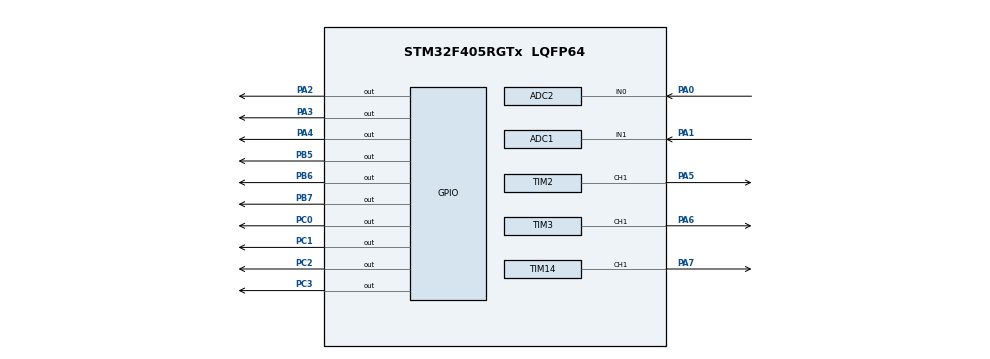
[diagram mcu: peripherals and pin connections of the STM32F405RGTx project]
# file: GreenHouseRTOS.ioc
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ADC1.Channel-0\#ChannelRegularConversion=ADC_CHANNEL_1
ADC1.ContinuousConvMode=ENABLE
ADC1.NbrOfConversionFlag=1
ADC1.Rank-0\#ChannelRegularConversion=1
ADC1.SamplingTime-0\#ChannelRegularConversion=ADC_SAMPLETIME_3CYCLES
ADC1.master=1
ADC2.Channel-0\#ChannelRegularConversion=ADC_CHANNEL_0
ADC2.NbrOfConversionFlag=1
ADC2.Rank-0\#ChannelRegularConversion=1
ADC2.SamplingTime-0\#ChannelRegularConversion=ADC_SAMPLETIME_3CYCLES
FREERTOS.Tasks01=defaultTask,0,128,StartDefaultTask,Default,NULL,Dynamic,NULL,NULL
FREERTOS.configCHECK_FOR_STACK_OVERFLOW=1
FREERTOS.configGENERATE_RUN_TIME_STATS=1
FREERTOS.configMAX_TASK_NAME_LEN=25
FREERTOS.configRECORD_STACK_HIGH_ADDRESS=1
FREERTOS.configUSE_IDLE_HOOK=1
FREERTOS.configUSE_NEWLIB_REENTRANT=1
FREERTOS.configUSE_STATS_FORMATTING_FUNCTIONS=1
FREERTOS.configUSE_TICK_HOOK=1
FREERTOS.configUSE_TRACE_FACILITY=1
Mcu.Family=STM32F4
Mcu.Name=STM32F405RGTx
Mcu.Package=LQFP64
NVIC.PriorityGroup=NVIC_PRIORITYGROUP_4
PA0-WKUP.Signal=ADCx_IN0
PA1.Signal=ADCx_IN1
PA2.Signal=GPIO_Output
PA3.Signal=GPIO_Output
PA4.Signal=GPIO_Output
PA5.Signal=S_TIM2_CH1_ETR
PA6.Signal=S_TIM3_CH1
PA7.Signal=S_TIM14_CH1
PB5.Signal=GPIO_Output
PB6.Signal=GPIO_Output
PB7.Signal=GPIO_Output
PC0.Signal=GPIO_Output
PC1.Signal=GPIO_Output
PC2.Signal=GPIO_Output
PC3.Signal=GPIO_Output
ProjectManager.HeapSize=0x200
ProjectManager.StackSize=0x400
ProjectManager.TargetToolchain=STM32CubeIDE
RCC.48MHZClocksFreq_Value=32000000
RCC.AHBCLKDivider=RCC_SYSCLK_DIV4
RCC.AHBFreq_Value=16000000
RCC.APB1CLKDivider=RCC_HCLK_DIV2
RCC.APB1Freq_Value=8000000
RCC.APB1TimFreq_Value=16000000
RCC.APB2Freq_Value=16000000
RCC.APB2TimFreq_Value=16000000
RCC.CortexFreq_Value=16000000
RCC.HCLKFreq_Value=16000000
RCC.HSE_VALUE=25000000
RCC.HSI_VALUE=16000000
RCC.LSE_VALUE=32768
RCC.PLLM=8
RCC.PLLN=64
RCC.SYSCLKFreq_VALUE=64000000
RCC.SYSCLKSource=RCC_SYSCLKSOURCE_PLLCLK
RCC.VCOOutputFreq_Value=128000000
SH.ADCx_IN0.0=ADC2_IN0,IN0
SH.ADCx_IN1.0=ADC1_IN1,IN1
SH.S_TIM14_CH1.0=TIM14_CH1,PWM Generation1 CH1
SH.S_TIM2_CH1_ETR.0=TIM2_CH1,PWM Generation1 CH1
SH.S_TIM3_CH1.0=TIM3_CH1,PWM Generation1 CH1
TIM12.Prescaler=15
TIM14.Channel=TIM_CHANNEL_1
TIM14.OCFastMode_PWM=TIM_OCFAST_ENABLE
TIM14.Period=799
TIM14.Prescaler=1
TIM2.Channel-PWM\ Generation1\ CH1=TIM_CHANNEL_1
TIM2.OCFastMode_PWM-PWM\ Generation1\ CH1=TIM_OCFAST_ENABLE
TIM2.Period=99
TIM2.Prescaler=15
TIM3.Channel-PWM\ Generation1\ CH1=TIM_CHANNEL_1
TIM3.OCFastMode_PWM-PWM\ Generation1\ CH1=TIM_OCFAST_ENABLE
TIM3.Period=9
TIM3.Prescaler=159
VP_FREERTOS_VS_CMSIS_V1.Mode=CMSIS_V1
VP_TIM12_VS_ClockSourceINT.Mode=Internal
VP_TIM14_VS_ClockSourceINT.Mode=Enable_Timer
VP_TIM2_VS_ClockSourceINT.Mode=Internal
VP_TIM3_VS_ClockSourceINT.Mode=Internal
board=custom

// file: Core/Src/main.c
/* USER CODE BEGIN Header */
/**
 ******************************************************************************
 * @file           : main.c
 * @brief          : Main program body
 ******************************************************************************
 * @attention
 *
 * Copyright (c) 2025 STMicroelectronics.
 * All rights reserved.
 *
 * This software is licensed under terms that can be found in the LICENSE file
 * in the root directory of this software component.
 * If no LICENSE file comes with this software, it is provided AS-IS.
 *
 ******************************************************************************
 */
/* USER CODE END Header */
#include "main.h"
#include "cmsis_os.h"

/* USER CODE BEGIN Includes */
#include<stdio.h>
#include "dht11.h"
#include "stdint.h"
#include "string.h"
#include "math.h"
/* USER CODE END Includes */

/* USER CODE BEGIN PD */
#define SOIL_MOISTURE_THRESHOLD 4050
#define LDR_HIGH_THRESHOLD 3200
#define LDR_MEDIUM_THRESHOLD 2500
#define LDR_LOW_THRESHOLD 1800
#define PWM_MAX 600
#define PWM_MEDIUM 400
#define PWM_LOW 200
#define PWM_MIN 0
#define PWM_INIT 0
/* USER CODE END PD */

ADC_HandleTypeDef hadc1;
ADC_HandleTypeDef hadc2;

TIM_HandleTypeDef htim2;
TIM_HandleTypeDef htim3;
TIM_HandleTypeDef htim12;
TIM_HandleTypeDef htim14;

osThreadId defaultTaskHandle;
/* USER CODE BEGIN PV */
TaskHandle_t x1Handle;
TaskHandle_t x2Handle;
TaskHandle_t x3Handle;
BaseType_t x1Return;
BaseType_t x2Return;
BaseType_t x3Return;

uint32_t analogIn = 0;
uint8_t check;
float moisture_percent = 0;
uint8_t DHT11_Read(DHT11_Data *data);
DHT11_Data dht;
uint8_t flag = 0;
uint32_t ldr_value = 0;
/* USER CODE END PV */

void SystemClock_Config(void);
static void MX_GPIO_Init(void);
static void MX_ADC1_Init(void);
static void MX_TIM2_Init(void);
static void MX_TIM3_Init(void);
static void MX_TIM14_Init(void);
static void MX_ADC2_Init(void);
static void MX_TIM12_Init(void);
void StartDefaultTask(void const * argument);

/* USER CODE BEGIN PFP */
void soilMoisture(void *pvParameters);
void tempHum(void *pvParameters);
void ldrMonitor(void *pvParameters);
void motor_config(void);
void led_pwm_config(void);
/* USER CODE END PFP */

int main(void)
{

  /* MCU Configuration--------------------------------------------------------*/

  /* Reset of all peripherals, Initializes the Flash interface and the Systick. */
  HAL_Init();

  /* Configure the system clock */
  SystemClock_Config();

  /* Initialize all configured peripherals */
  MX_GPIO_Init();
  MX_ADC1_Init();
  MX_TIM2_Init();
  MX_TIM3_Init();
  MX_TIM14_Init();
  MX_ADC2_Init();
  MX_TIM12_Init();
  /* USER CODE BEGIN 2 */
	HAL_ADC_Start(&hadc1);
	HAL_ADC_Start(&hadc2);
	HAL_TIM_PWM_Start(&htim3, TIM_CHANNEL_1);
	HAL_TIM_PWM_Start(&htim14, TIM_CHANNEL_1);
	HAL_TIM_PWM_Start(&htim2, TIM_CHANNEL_1); // Start PWM

	HAL_TIM_Base_Start(&htim12);
	DWT_Init();

	motor_config();
	led_pwm_config();
  /* USER CODE END 2 */

  /* Create the thread(s) */
  /* definition and creation of defaultTask */
  osThreadDef(defaultTask, StartDefaultTask, osPriorityNormal, 0, 128);
  defaultTaskHandle = osThreadCreate(osThread(defaultTask), NULL);

  /* USER CODE BEGIN RTOS_THREADS */
	/* add threads, ... */
	x1Return = xTaskCreate(soilMoisture, "SOIL TASK",
	configMINIMAL_STACK_SIZE * 3,
	NULL, 2, &x1Handle);

	x2Return = xTaskCreate(tempHum, "T&H TASK",
	configMINIMAL_STACK_SIZE * 3,
	NULL, 1, &x2Handle);

	x3Return = xTaskCreate(ldrMonitor, "LIGHT TASK",
	configMINIMAL_STACK_SIZE * 3,
	NULL, 1, &x3Handle);
  /* USER CODE END RTOS_THREADS */

  /* Start scheduler */
  osKernelStart();

  /* We should never get here as control is now taken by the scheduler */
  /* Infinite loop */
	while (1) {

	}
}

void SystemClock_Config(void)
{
	RCC_OscInitTypeDef RCC_OscInitStruct = {0};
	  RCC_ClkInitTypeDef RCC_ClkInitStruct = {0};

	  /** Configure the main internal regulator output voltage
	  */
	  __HAL_RCC_PWR_CLK_ENABLE();
	  __HAL_PWR_VOLTAGESCALING_CONFIG(PWR_REGULATOR_VOLTAGE_SCALE1);

	  /** Initializes the RCC Oscillators according to the specified parameters
	  * in the RCC_OscInitTypeDef structure.
	  */
	  RCC_OscInitStruct.OscillatorType = RCC_OSCILLATORTYPE_HSI;
	  RCC_OscInitStruct.HSIState = RCC_HSI_ON;
	  RCC_OscInitStruct.HSICalibrationValue = RCC_HSICALIBRATION_DEFAULT;
	  RCC_OscInitStruct.PLL.PLLState = RCC_PLL_ON;
	  RCC_OscInitStruct.PLL.PLLSource = RCC_PLLSOURCE_HSI;
	  RCC_OscInitStruct.PLL.PLLM = 8;
	  RCC_OscInitStruct.PLL.PLLN = 84;
	  RCC_OscInitStruct.PLL.PLLP = RCC_PLLP_DIV4;
	  RCC_OscInitStruct.PLL.PLLQ = 4;
	  if (HAL_RCC_OscConfig(&RCC_OscInitStruct) != HAL_OK)
	  {
	    Error_Handler();
	  }

	  /** Initializes the CPU, AHB and APB buses clocks
	  */
	  RCC_ClkInitStruct.ClockType = RCC_CLOCKTYPE_HCLK|RCC_CLOCKTYPE_SYSCLK
	                              |RCC_CLOCKTYPE_PCLK1|RCC_CLOCKTYPE_PCLK2;
	  RCC_ClkInitStruct.SYSCLKSource = RCC_SYSCLKSOURCE_PLLCLK;
	  RCC_ClkInitStruct.AHBCLKDivider = RCC_SYSCLK_DIV1;
	  RCC_ClkInitStruct.APB1CLKDivider = RCC_HCLK_DIV1;
	  RCC_ClkInitStruct.APB2CLKDivider = RCC_HCLK_DIV1;

	  if (HAL_RCC_ClockConfig(&RCC_ClkInitStruct, FLASH_LATENCY_1) != HAL_OK)
	  {
	    Error_Handler();
	  }

}

static void MX_ADC1_Init(void)
{

  ADC_ChannelConfTypeDef sConfig = {0};

  /** Configure the global features of the ADC (Clock, Resolution, Data Alignment and number of conversion)
  */
  hadc1.Instance = ADC1;
  hadc1.Init.ClockPrescaler = ADC_CLOCK_SYNC_PCLK_DIV2;
  hadc1.Init.Resolution = ADC_RESOLUTION_12B;
  hadc1.Init.ScanConvMode = DISABLE;
  hadc1.Init.ContinuousConvMode = ENABLE;
  hadc1.Init.DiscontinuousConvMode = DISABLE;
  hadc1.Init.ExternalTrigConvEdge = ADC_EXTERNALTRIGCONVEDGE_NONE;
  hadc1.Init.ExternalTrigConv = ADC_SOFTWARE_START;
  hadc1.Init.DataAlign = ADC_DATAALIGN_RIGHT;
  hadc1.Init.NbrOfConversion = 1;
  hadc1.Init.DMAContinuousRequests = DISABLE;
  hadc1.Init.EOCSelection = ADC_EOC_SINGLE_CONV;
  if (HAL_ADC_Init(&hadc1) != HAL_OK)
  {
    Error_Handler();
  }

  /** Configure for the selected ADC regular channel its corresponding rank in the sequencer and its sample time.
  */
  sConfig.Channel = ADC_CHANNEL_1;
  sConfig.Rank = 1;
  sConfig.SamplingTime = ADC_SAMPLETIME_3CYCLES;
  if (HAL_ADC_ConfigChannel(&hadc1, &sConfig) != HAL_OK)
  {
    Error_Handler();
  }

}

static void MX_ADC2_Init(void)
{

  ADC_ChannelConfTypeDef sConfig = {0};

  /** Configure the global features of the ADC (Clock, Resolution, Data Alignment and number of conversion)
  */
  hadc2.Instance = ADC2;
  hadc2.Init.ClockPrescaler = ADC_CLOCK_SYNC_PCLK_DIV2;
  hadc2.Init.Resolution = ADC_RESOLUTION_12B;
  hadc2.Init.ScanConvMode = DISABLE;
  hadc2.Init.ContinuousConvMode = DISABLE;
  hadc2.Init.DiscontinuousConvMode = DISABLE;
  hadc2.Init.ExternalTrigConvEdge = ADC_EXTERNALTRIGCONVEDGE_NONE;
  hadc2.Init.ExternalTrigConv = ADC_SOFTWARE_START;
  hadc2.Init.DataAlign = ADC_DATAALIGN_RIGHT;
  hadc2.Init.NbrOfConversion = 1;
  hadc2.Init.DMAContinuousRequests = DISABLE;
  hadc2.Init.EOCSelection = ADC_EOC_SINGLE_CONV;
  if (HAL_ADC_Init(&hadc2) != HAL_OK)
  {
    Error_Handler();
  }

  /** Configure for the selected ADC regular channel its corresponding rank in the sequencer and its sample time.
  */
  sConfig.Channel = ADC_CHANNEL_0;
  sConfig.Rank = 1;
  sConfig.SamplingTime = ADC_SAMPLETIME_3CYCLES;
  if (HAL_ADC_ConfigChannel(&hadc2, &sConfig) != HAL_OK)
  {
    Error_Handler();
  }

}

static void MX_TIM2_Init(void)
{

  TIM_ClockConfigTypeDef sClockSourceConfig = {0};
  TIM_MasterConfigTypeDef sMasterConfig = {0};
  TIM_OC_InitTypeDef sConfigOC = {0};

  htim2.Instance = TIM2;
  htim2.Init.Prescaler = 15;
  htim2.Init.CounterMode = TIM_COUNTERMODE_UP;
  htim2.Init.Period = 99;
  htim2.Init.ClockDivision = TIM_CLOCKDIVISION_DIV1;
  htim2.Init.AutoReloadPreload = TIM_AUTORELOAD_PRELOAD_DISABLE;
  if (HAL_TIM_Base_Init(&htim2) != HAL_OK)
  {
    Error_Handler();
  }
  sClockSourceConfig.ClockSource = TIM_CLOCKSOURCE_INTERNAL;
  if (HAL_TIM_ConfigClockSource(&htim2, &sClockSourceConfig) != HAL_OK)
  {
    Error_Handler();
  }
  if (HAL_TIM_PWM_Init(&htim2) != HAL_OK)
  {
    Error_Handler();
  }
  sMasterConfig.MasterOutputTrigger = TIM_TRGO_RESET;
  sMasterConfig.MasterSlaveMode = TIM_MASTERSLAVEMODE_DISABLE;
  if (HAL_TIMEx_MasterConfigSynchronization(&htim2, &sMasterConfig) != HAL_OK)
  {
    Error_Handler();
  }
  sConfigOC.OCMode = TIM_OCMODE_PWM1;
  sConfigOC.Pulse = 0;
  sConfigOC.OCPolarity = TIM_OCPOLARITY_HIGH;
  sConfigOC.OCFastMode = TIM_OCFAST_ENABLE;
  if (HAL_TIM_PWM_ConfigChannel(&htim2, &sConfigOC, TIM_CHANNEL_1) != HAL_OK)
  {
    Error_Handler();
  }
  HAL_TIM_MspPostInit(&htim2);

}

static void MX_TIM3_Init(void)
{

  TIM_ClockConfigTypeDef sClockSourceConfig = {0};
  TIM_MasterConfigTypeDef sMasterConfig = {0};
  TIM_OC_InitTypeDef sConfigOC = {0};

  htim3.Instance = TIM3;
  htim3.Init.Prescaler = 159;
  htim3.Init.CounterMode = TIM_COUNTERMODE_UP;
  htim3.Init.Period = 9;
  htim3.Init.ClockDivision = TIM_CLOCKDIVISION_DIV1;
  htim3.Init.AutoReloadPreload = TIM_AUTORELOAD_PRELOAD_DISABLE;
  if (HAL_TIM_Base_Init(&htim3) != HAL_OK)
  {
    Error_Handler();
  }
  sClockSourceConfig.ClockSource = TIM_CLOCKSOURCE_INTERNAL;
  if (HAL_TIM_ConfigClockSource(&htim3, &sClockSourceConfig) != HAL_OK)
  {
    Error_Handler();
  }
  if (HAL_TIM_PWM_Init(&htim3) != HAL_OK)
  {
    Error_Handler();
  }
  sMasterConfig.MasterOutputTrigger = TIM_TRGO_RESET;
  sMasterConfig.MasterSlaveMode = TIM_MASTERSLAVEMODE_DISABLE;
  if (HAL_TIMEx_MasterConfigSynchronization(&htim3, &sMasterConfig) != HAL_OK)
  {
    Error_Handler();
  }
  sConfigOC.OCMode = TIM_OCMODE_PWM1;
  sConfigOC.Pulse = 0;
  sConfigOC.OCPolarity = TIM_OCPOLARITY_HIGH;
  sConfigOC.OCFastMode = TIM_OCFAST_ENABLE;
  if (HAL_TIM_PWM_ConfigChannel(&htim3, &sConfigOC, TIM_CHANNEL_1) != HAL_OK)
  {
    Error_Handler();
  }
  HAL_TIM_MspPostInit(&htim3);

}

static void MX_TIM12_Init(void)
{

  TIM_ClockConfigTypeDef sClockSourceConfig = {0};

  htim12.Instance = TIM12;
  htim12.Init.Prescaler = 15;
  htim12.Init.CounterMode = TIM_COUNTERMODE_UP;
  htim12.Init.Period = 65535;
  htim12.Init.ClockDivision = TIM_CLOCKDIVISION_DIV1;
  htim12.Init.AutoReloadPreload = TIM_AUTORELOAD_PRELOAD_DISABLE;
  if (HAL_TIM_Base_Init(&htim12) != HAL_OK)
  {
    Error_Handler();
  }
  sClockSourceConfig.ClockSource = TIM_CLOCKSOURCE_INTERNAL;
  if (HAL_TIM_ConfigClockSource(&htim12, &sClockSourceConfig) != HAL_OK)
  {
    Error_Handler();
  }

}

static void MX_TIM14_Init(void)
{

  TIM_OC_InitTypeDef sConfigOC = {0};

  htim14.Instance = TIM14;
  htim14.Init.Prescaler = 1;
  htim14.Init.CounterMode = TIM_COUNTERMODE_UP;
  htim14.Init.Period = 799;
  htim14.Init.ClockDivision = TIM_CLOCKDIVISION_DIV1;
  htim14.Init.AutoReloadPreload = TIM_AUTORELOAD_PRELOAD_DISABLE;
  if (HAL_TIM_Base_Init(&htim14) != HAL_OK)
  {
    Error_Handler();
  }
  if (HAL_TIM_PWM_Init(&htim14) != HAL_OK)
  {
    Error_Handler();
  }
  sConfigOC.OCMode = TIM_OCMODE_PWM1;
  sConfigOC.Pulse = 0;
  sConfigOC.OCPolarity = TIM_OCPOLARITY_HIGH;
  sConfigOC.OCFastMode = TIM_OCFAST_ENABLE;
  if (HAL_TIM_PWM_ConfigChannel(&htim14, &sConfigOC, TIM_CHANNEL_1) != HAL_OK)
  {
    Error_Handler();
  }
  HAL_TIM_MspPostInit(&htim14);

}

static void MX_GPIO_Init(void)
{
  GPIO_InitTypeDef GPIO_InitStruct = {0};

  /* GPIO Ports Clock Enable */
  __HAL_RCC_GPIOC_CLK_ENABLE();
  __HAL_RCC_GPIOA_CLK_ENABLE();
  __HAL_RCC_GPIOB_CLK_ENABLE();

  /*Configure GPIO pin Output Level */
  HAL_GPIO_WritePin(GPIOC, GPIO_PIN_0|GPIO_PIN_1|GPIO_PIN_2|GPIO_PIN_3, GPIO_PIN_RESET);

  /*Configure GPIO pin Output Level */
  HAL_GPIO_WritePin(GPIOA, GPIO_PIN_2|GPIO_PIN_3|GPIO_PIN_4, GPIO_PIN_RESET);

  /*Configure GPIO pin Output Level */
  HAL_GPIO_WritePin(GPIOB, GPIO_PIN_5|GPIO_PIN_6|GPIO_PIN_7, GPIO_PIN_RESET);

  /*Configure GPIO pins : PC0 PC1 PC2 PC3 */
  GPIO_InitStruct.Pin = GPIO_PIN_0|GPIO_PIN_1|GPIO_PIN_2|GPIO_PIN_3;
  GPIO_InitStruct.Mode = GPIO_MODE_OUTPUT_PP;
  GPIO_InitStruct.Pull = GPIO_NOPULL;
  GPIO_InitStruct.Speed = GPIO_SPEED_FREQ_LOW;
  HAL_GPIO_Init(GPIOC, &GPIO_InitStruct);

  /*Configure GPIO pins : PA2 PA3 PA4 */
  GPIO_InitStruct.Pin = GPIO_PIN_2|GPIO_PIN_3|GPIO_PIN_4;
  GPIO_InitStruct.Mode = GPIO_MODE_OUTPUT_PP;
  GPIO_InitStruct.Pull = GPIO_NOPULL;
  GPIO_InitStruct.Speed = GPIO_SPEED_FREQ_LOW;
  HAL_GPIO_Init(GPIOA, &GPIO_InitStruct);

  /*Configure GPIO pins : PB5 PB6 PB7 */
  GPIO_InitStruct.Pin = GPIO_PIN_5|GPIO_PIN_6|GPIO_PIN_7;
  GPIO_InitStruct.Mode = GPIO_MODE_OUTPUT_PP;
  GPIO_InitStruct.Pull = GPIO_NOPULL;
  GPIO_InitStruct.Speed = GPIO_SPEED_FREQ_LOW;
  HAL_GPIO_Init(GPIOB, &GPIO_InitStruct);

}

/* USER CODE BEGIN 4 */
void motor_config(void) {
	HAL_GPIO_WritePin(GPIOA, GPIO_PIN_4, GPIO_PIN_SET); //STBY
	HAL_GPIO_WritePin(GPIOC, GPIO_PIN_2, GPIO_PIN_SET); //AIN1
	HAL_GPIO_WritePin(GPIOC, GPIO_PIN_3, GPIO_PIN_RESET); //AIN2

	HAL_TIM_PWM_Start(&htim14, TIM_CHANNEL_1);

	__HAL_TIM_SET_COMPARE(&htim14, TIM_CHANNEL_1, 300);
}
void led_pwm_config(void) {
	HAL_GPIO_WritePin(GPIOB, GPIO_PIN_5, GPIO_PIN_SET); // STBY
	HAL_GPIO_WritePin(GPIOB, GPIO_PIN_6, GPIO_PIN_SET); // AIN1
	HAL_GPIO_WritePin(GPIOB, GPIO_PIN_7, GPIO_PIN_RESET); // AIN2

	HAL_TIM_PWM_Start(&htim2, TIM_CHANNEL_1); // Start PWM
	__HAL_TIM_SET_COMPARE(&htim2, TIM_CHANNEL_1, 0); // Start with 0 duty
}
void soilMoisture(void *pvParameters) {
	for (;;) {
		HAL_ADC_Start(&hadc1);
		HAL_ADC_PollForConversion(&hadc1, HAL_MAX_DELAY);
		analogIn = HAL_ADC_GetValue(&hadc1);

		if (analogIn > 4050) {
			check = 1;
			HAL_GPIO_WritePin(GPIOA, GPIO_PIN_3, GPIO_PIN_SET); // STANDBY
			HAL_GPIO_WritePin(GPIOC, GPIO_PIN_0, GPIO_PIN_SET); // AIN1
			HAL_GPIO_WritePin(GPIOC, GPIO_PIN_1, GPIO_PIN_RESET); // AIN2
			__HAL_TIM_SET_COMPARE(&htim3, TIM_CHANNEL_1, 500);
		} else {
			__HAL_TIM_SET_COMPARE(&htim3, TIM_CHANNEL_1, 0);
			HAL_GPIO_WritePin(GPIOA, GPIO_PIN_3, GPIO_PIN_RESET); // STANDBY
		}

		vTaskDelay(pdMS_TO_TICKS(500)); // run every 500ms
	}
}

void tempHum(void *pvParameters) {
	for (;;) {
		if (DHT11_GetData(GPIOA, GPIO_PIN_2, &dht)) {

			// ✅ Motor ON only if BOTH temperature >= 27 AND humidity >= 73
			if ((dht.Temperature >= 27 && dht.Humidity >= 73) && flag != 1) {
				uint16_t pwm_values[] = { 200, 400, 600 };
				for (int i = 0; i < 3; i++) {
					__HAL_TIM_SET_COMPARE(&htim14, TIM_CHANNEL_1,
							pwm_values[i]);
					vTaskDelay(pdMS_TO_TICKS(2000));
				}
				flag = 1; // Motor is ON
			}

			// ✅ Motor OFF gradually if EITHER temp < 27 OR humidity < 73
			else if ((dht.Temperature < 27 && dht.Humidity < 73) && flag == 1) {
				uint16_t pwm_values[] = { 600, 400, 200, 0 };
				for (int i = 0; i < 4; i++) {
					__HAL_TIM_SET_COMPARE(&htim14, TIM_CHANNEL_1,
							pwm_values[i]);
					vTaskDelay(pdMS_TO_TICKS(2000));
				}
				flag = 0; // Motor is OFF
			}
		}

		vTaskDelay(pdMS_TO_TICKS(100)); // Check every 2s
	}
}

void ldrMonitor(void *pvParameters) {
	for (;;) {
		HAL_ADC_Start(&hadc2);
		HAL_ADC_PollForConversion(&hadc2, 10);
		ldr_value = HAL_ADC_GetValue(&hadc2);

		if (ldr_value >= 3200) {
			__HAL_TIM_SET_COMPARE(&htim2, TIM_CHANNEL_1, 100);
		} else if (ldr_value >= 2500) {
			__HAL_TIM_SET_COMPARE(&htim2, TIM_CHANNEL_1, 50);
		} else if (ldr_value >= 1800) {
			__HAL_TIM_SET_COMPARE(&htim2, TIM_CHANNEL_1, 25);
		} else {
			__HAL_TIM_SET_COMPARE(&htim2, TIM_CHANNEL_1, 0);
		}

		vTaskDelay(pdMS_TO_TICKS(100)); // smoother update
	}
}
void configureTimerForRunTimeStats(void) {
	HAL_TIM_Base_Start(&htim12); // Timer already started
}

uint32_t getRunTimeCounterValue(void) {
	return __HAL_TIM_GET_COUNTER(&htim12);
}
/* USER CODE END 4 */

void StartDefaultTask(void const * argument)
{
  /* USER CODE BEGIN 5 */

	/* Infinite loop */
	for (;;) {
		//a++;
		osDelay(1);
	}
  /* USER CODE END 5 */
}

void Error_Handler(void)
{
	__disable_irq();
	while (1) {
	}
}

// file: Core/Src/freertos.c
/* USER CODE BEGIN Header */
/**
  ******************************************************************************
  * File Name          : freertos.c
  * Description        : Code for freertos applications
  ******************************************************************************
  * @attention
  *
  * Copyright (c) 2025 STMicroelectronics.
  * All rights reserved.
  *
  * This software is licensed under terms that can be found in the LICENSE file
  * in the root directory of this software component.
  * If no LICENSE file comes with this software, it is provided AS-IS.
  *
  ******************************************************************************
  */
/* USER CODE END Header */

#include "FreeRTOS.h"
#include "task.h"
#include "main.h"

/* GetIdleTaskMemory prototype (linked to static allocation support) */
void vApplicationGetIdleTaskMemory( StaticTask_t **ppxIdleTaskTCBBuffer, StackType_t **ppxIdleTaskStackBuffer, uint32_t *pulIdleTaskStackSize );

/* Hook prototypes */
void configureTimerForRunTimeStats(void);
unsigned long getRunTimeCounterValue(void);
void vApplicationIdleHook(void);
void vApplicationTickHook(void);
void vApplicationStackOverflowHook(xTaskHandle xTask, signed char *pcTaskName);

/* USER CODE BEGIN 1 */
/* Functions needed when configGENERATE_RUN_TIME_STATS is on */
__weak void configureTimerForRunTimeStats(void)
{

}

__weak unsigned long getRunTimeCounterValue(void)
{
return 0;
}
/* USER CODE END 1 */

/* USER CODE BEGIN 2 */
__weak void vApplicationIdleHook( void )
{
   /* vApplicationIdleHook() will only be called if configUSE_IDLE_HOOK is set
   to 1 in FreeRTOSConfig.h. It will be called on each iteration of the idle
   task. It is essential that code added to this hook function never attempts
   to block in any way (for example, call xQueueReceive() with a block time
   specified, or call vTaskDelay()). If the application makes use of the
   vTaskDelete() API function (as this demo application does) then it is also
   important that vApplicationIdleHook() is permitted to return to its calling
   function, because it is the responsibility of the idle task to clean up
   memory allocated by the kernel to any task that has since been deleted. */
}
/* USER CODE END 2 */

/* USER CODE BEGIN 3 */
__weak void vApplicationTickHook( void )
{
   /* This function will be called by each tick interrupt if
   configUSE_TICK_HOOK is set to 1 in FreeRTOSConfig.h. User code can be
   added here, but the tick hook is called from an interrupt context, so
   code must not attempt to block, and only the interrupt safe FreeRTOS API
   functions can be used (those that end in FromISR()). */
}
/* USER CODE END 3 */

/* USER CODE BEGIN 4 */
__weak void vApplicationStackOverflowHook(xTaskHandle xTask, signed char *pcTaskName)
{
   /* Run time stack overflow checking is performed if
   configCHECK_FOR_STACK_OVERFLOW is defined to 1 or 2. This hook function is
   called if a stack overflow is detected. */
}
/* USER CODE END 4 */

/* USER CODE BEGIN GET_IDLE_TASK_MEMORY */
static StaticTask_t xIdleTaskTCBBuffer;
static StackType_t xIdleStack[configMINIMAL_STACK_SIZE];

void vApplicationGetIdleTaskMemory( StaticTask_t **ppxIdleTaskTCBBuffer, StackType_t **ppxIdleTaskStackBuffer, uint32_t *pulIdleTaskStackSize )
{
  *ppxIdleTaskTCBBuffer = &xIdleTaskTCBBuffer;
  *ppxIdleTaskStackBuffer = &xIdleStack[0];
  *pulIdleTaskStackSize = configMINIMAL_STACK_SIZE;
  /* place for user code */
}
/* USER CODE END GET_IDLE_TASK_MEMORY */
